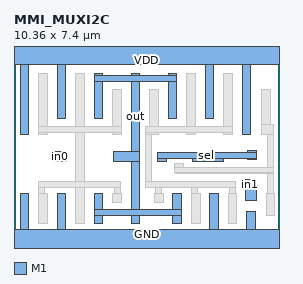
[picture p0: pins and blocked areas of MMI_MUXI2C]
MACRO MMI_MUXI2C
	CLASS CORE ;
	FOREIGN MMI_MUXI2C 0 0 ;
	SIZE 10.36 BY 7.4 ;
	SYMMETRY X Y ;
	SITE CORE1 ;
	PIN out
		DIRECTION output ;
		USE SIGNAL ;
		PORT
			LAYER M1 ;
			RECT 3.12 6.475 3.46 6.57 ;
			LAYER M1 ;
			RECT 4.56 6.475 4.9 6.57 ;
			LAYER M1 ;
			RECT 6 6.475 6.34 6.57 ;
			LAYER M1 ;
			RECT 3.12 6.245 6.34 6.475 ;
			LAYER M1 ;
			RECT 3.12 4.815 3.46 6.245 ;
			LAYER M1 ;
			RECT 4.56 3.525 4.9 6.245 ;
			LAYER M1 ;
			RECT 6 4.815 6.34 6.245 ;
			LAYER M1 ;
			RECT 3.875 3.13 4.9 3.525 ;
			LAYER M1 ;
			RECT 3.12 1.26 3.46 1.88 ;
			LAYER M1 ;
			RECT 4.56 1.26 4.9 3.13 ;
			LAYER M1 ;
			RECT 6.185 1.26 6.525 1.88 ;
			LAYER M1 ;
			RECT 3.12 1.03 6.525 1.26 ;
			LAYER M1 ;
			RECT 3.12 0.73 3.46 1.03 ;
			LAYER M1 ;
			RECT 4.56 0.73 4.9 1.03 ;
			LAYER M1 ;
			RECT 6.185 0.73 6.525 1.03 ;
		END
		AntennaDiffArea 5.9697 ;
	END out
	PIN sel
		DIRECTION input ;
		USE SIGNAL ;
		PORT
			LAYER M1 ;
			RECT 9.1 3.5 9.44 3.545 ;
			LAYER M1 ;
			RECT 5.6 3.49 9.44 3.5 ;
			LAYER M1 ;
			RECT 5.59 3.27 9.44 3.49 ;
			LAYER M1 ;
			RECT 5.59 3.15 5.93 3.27 ;
			LAYER M1 ;
			RECT 6.94 3.135 8.14 3.27 ;
			LAYER M1 ;
			RECT 9.1 3.205 9.44 3.27 ;
		END
		AntennaGateArea 2.4867 ;
	END sel
	PIN in1
		DIRECTION input ;
		USE SIGNAL ;
		PORT
			LAYER M1 ;
			RECT 8.915 2.03 9.46 2.43 ;
			LAYER M1 ;
			RECT 9.035 1.61 9.46 2.03 ;
		END
		AntennaGateArea 1.9899 ;
	END in1
	PIN GND
		DIRECTION inout ;
		USE GROUND ;
		PORT
			LAYER M1 ;
			RECT 0.24 0.5 0.58 1.88 ;
			LAYER M1 ;
			RECT 1.68 0.5 2.02 1.88 ;
			LAYER M1 ;
			RECT 7.625 0.5 7.965 1.88 ;
			LAYER M1 ;
			RECT 9.065 0.5 9.405 1.175 ;
			LAYER M1 ;
			RECT 0 -0.5 10.36 0.5 ;
		END
	END GND
	PIN VDD
		DIRECTION inout ;
		USE POWER ;
		PORT
			LAYER M1 ;
			RECT 0 6.9 10.36 7.9 ;
			LAYER M1 ;
			RECT 0.24 4.195 0.58 6.9 ;
			LAYER M1 ;
			RECT 1.68 4.815 2.02 6.9 ;
			LAYER M1 ;
			RECT 7.44 4.815 7.78 6.9 ;
			LAYER M1 ;
			RECT 8.88 4.195 9.22 6.9 ;
		END
	END VDD
	PIN in0
		DIRECTION input ;
		USE SIGNAL ;
		PORT
			LAYER M1 ;
			RECT 1.515 3.125 2.06 3.53 ;
		END
		AntennaGateArea 1.9899 ;
	END in0
	OBS
		LAYER M1 ;
		RECT 0.96 4.5 1.3 6.57 ;
		LAYER M1 ;
		RECT 2.4 4.5 2.74 6.57 ;
		LAYER M1 ;
		RECT 3.84 4.5 4.18 5.945 ;
		LAYER M1 ;
		RECT 0.96 4.27 4.18 4.5 ;
		LAYER M1 ;
		RECT 0.96 4.195 1.3 4.27 ;
		LAYER M1 ;
		RECT 2.4 2.36 2.74 4.27 ;
		LAYER M1 ;
		RECT 3.84 4.195 4.18 4.27 ;
		LAYER M1 ;
		RECT 5.28 4.495 5.62 5.945 ;
		LAYER M1 ;
		RECT 6.72 4.495 7.06 6.57 ;
		LAYER M1 ;
		RECT 8.16 4.495 8.5 6.57 ;
		LAYER M1 ;
		RECT 0.96 2.13 4.14 2.36 ;
		LAYER M1 ;
		RECT 0.96 1.88 1.19 2.13 ;
		LAYER M1 ;
		RECT 0.96 0.73 1.3 1.88 ;
		LAYER M1 ;
		RECT 2.4 0.73 2.74 2.13 ;
		LAYER M1 ;
		RECT 3.91 1.88 4.14 2.13 ;
		LAYER M1 ;
		RECT 3.84 1.54 4.18 1.88 ;
		LAYER M1 ;
		RECT 5.13 4.265 8.5 4.495 ;
		LAYER M1 ;
		RECT 5.13 4.195 5.62 4.265 ;
		LAYER M1 ;
		RECT 6.72 4.195 7.06 4.265 ;
		LAYER M1 ;
		RECT 8.16 4.195 8.5 4.265 ;
		LAYER M1 ;
		RECT 9.64 4.595 9.98 5.955 ;
		LAYER M1 ;
		RECT 9.64 4.195 10.1 4.595 ;
		LAYER M1 ;
		RECT 5.13 2.34 5.36 4.195 ;
		LAYER M1 ;
		RECT 6.26 2.89 6.6 3.04 ;
		LAYER M1 ;
		RECT 9.87 2.89 10.1 4.195 ;
		LAYER M1 ;
		RECT 6.26 2.7 10.1 2.89 ;
		LAYER M1 ;
		RECT 6.29 2.66 10.1 2.7 ;
		LAYER M1 ;
		RECT 5.13 2.11 8.625 2.34 ;
		LAYER M1 ;
		RECT 5.52 1.88 5.75 2.11 ;
		LAYER M1 ;
		RECT 6.91 1.88 7.14 2.11 ;
		LAYER M1 ;
		RECT 8.395 1.88 8.625 2.11 ;
		LAYER M1 ;
		RECT 5.465 1.54 5.805 1.88 ;
		LAYER M1 ;
		RECT 6.905 0.73 7.245 1.88 ;
		LAYER M1 ;
		RECT 8.345 0.73 8.685 1.88 ;
		LAYER M1 ;
		RECT 9.87 1.88 10.1 2.66 ;
		LAYER M1 ;
		RECT 9.825 1.04 10.165 1.88 ;
	END
END MMI_MUXI2C
